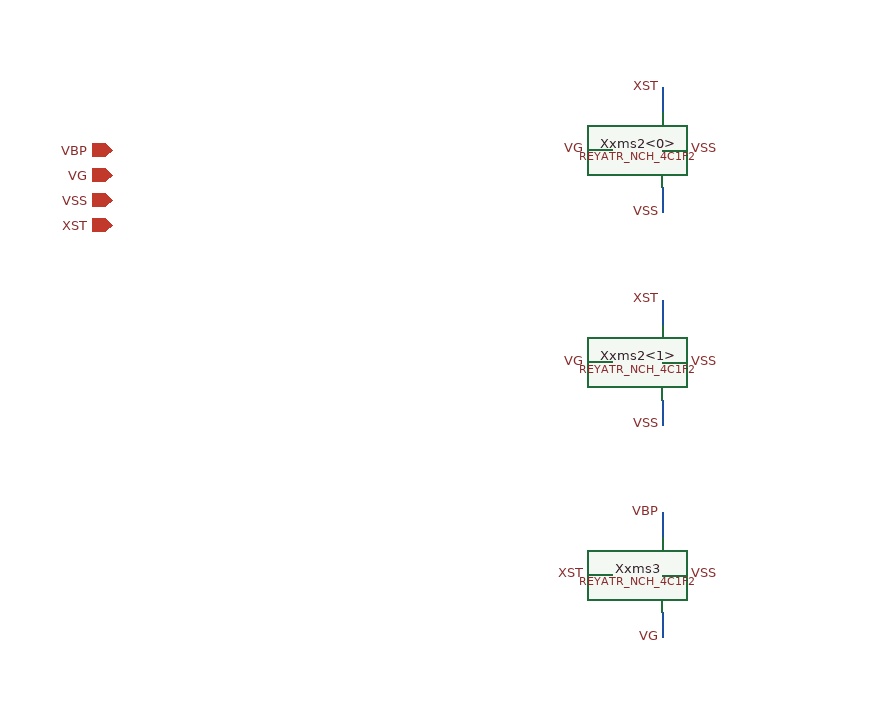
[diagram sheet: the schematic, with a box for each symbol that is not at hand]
v {xschem version=3.0.0 file_version=1.2 }
G {}
K {}
V {}
S {}
E {}
C {devices/iopin.sym} 0 0 0 0 {name=p0 lab=VBP}
C {devices/iopin.sym} 0 20 0 0 {name=p1 lab=VG}
C {devices/iopin.sym} 0 40 0 0 {name=p2 lab=VSS}
C {devices/iopin.sym} 0 60 0 0 {name=p3 lab=XST}
C {REY_ATR_SKY130A/REYATR_NCH_4C1F2.sym} 400 0 0 0 {name=Xxms2<0>}
N 440.0 -50.0 440.0 -30.0 {lab=XST}
C {devices/lab_pin.sym} 440.0 -50.0 3 0 {name=l0 sig_type=std_logic lab=XST }
N 380.0 0.0 400.0 0.0 {lab=VG}
C {devices/lab_pin.sym} 380.0 0.0 0 0 {name=l1 sig_type=std_logic lab=VG }
N 440.0 50.0 440.0 30.0 {lab=VSS}
C {devices/lab_pin.sym} 440.0 50.0 1 0 {name=l2 sig_type=std_logic lab=VSS }
N 460.0 0.0 440.0 0.0 {lab=VSS}
C {devices/lab_pin.sym} 460.0 0.0 2 0 {name=l3 sig_type=std_logic lab=VSS }
C {REY_ATR_SKY130A/REYATR_NCH_4C1F2.sym} 400 170 0 0 {name=Xxms2<1>}
N 440.0 120.0 440.0 140.0 {lab=XST}
C {devices/lab_pin.sym} 440.0 120.0 3 0 {name=l4 sig_type=std_logic lab=XST }
N 380.0 170.0 400.0 170.0 {lab=VG}
C {devices/lab_pin.sym} 380.0 170.0 0 0 {name=l5 sig_type=std_logic lab=VG }
N 440.0 220.0 440.0 200.0 {lab=VSS}
C {devices/lab_pin.sym} 440.0 220.0 1 0 {name=l6 sig_type=std_logic lab=VSS }
N 460.0 170.0 440.0 170.0 {lab=VSS}
C {devices/lab_pin.sym} 460.0 170.0 2 0 {name=l7 sig_type=std_logic lab=VSS }
C {REY_ATR_SKY130A/REYATR_NCH_4C1F2.sym} 400 340 0 0 {name=Xxms3}
N 440.0 290.0 440.0 310.0 {lab=VBP}
C {devices/lab_pin.sym} 440.0 290.0 3 0 {name=l8 sig_type=std_logic lab=VBP }
N 380.0 340.0 400.0 340.0 {lab=XST}
C {devices/lab_pin.sym} 380.0 340.0 0 0 {name=l9 sig_type=std_logic lab=XST }
N 440.0 390.0 440.0 370.0 {lab=VG}
C {devices/lab_pin.sym} 440.0 390.0 1 0 {name=l10 sig_type=std_logic lab=VG }
N 460.0 340.0 440.0 340.0 {lab=VSS}
C {devices/lab_pin.sym} 460.0 340.0 2 0 {name=l11 sig_type=std_logic lab=VSS }
